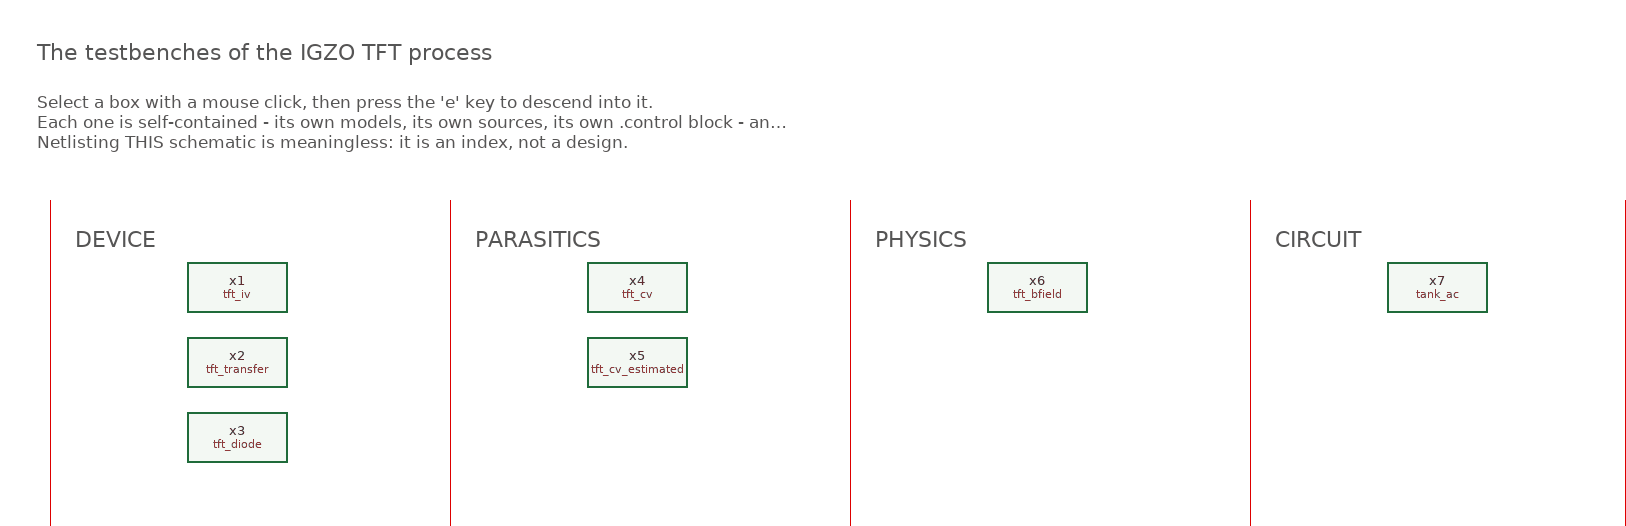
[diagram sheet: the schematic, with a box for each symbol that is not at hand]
v {xschem version=3.4.5 file_version=1.2

* The testbenches of the UCI/INRF IGZO TFT process (igzo_mmm_lab).
*
* Licensed under the Apache License, Version 2.0 (the "License");
* you may not use this file except in compliance with the License.
* You may obtain a copy of the License at
*
*     http://www.apache.org/licenses/LICENSE-2.0
*
* GENERATED by scripts/build_test_symbols.py - do not edit by hand.
}
G {}
K {}
V {}
S {}
E {}
L 7 40 -710 40 -80 {}
T {DEVICE} 60 -690 0 0 0.7 0.7 {}
L 7 360 -710 360 -80 {}
T {PARASITICS} 380 -690 0 0 0.7 0.7 {}
L 7 680 -710 680 -80 {}
T {PHYSICS} 700 -690 0 0 0.7 0.7 {}
L 7 1000 -710 1000 -80 {}
T {CIRCUIT} 1020 -690 0 0 0.7 0.7 {}
L 7 1300 -710 1300 -80 {}
T {The testbenches of the IGZO TFT process} 30 -840 0 0 0.8 0.8 {layer=8}
T {Select a box with a mouse click, then press the 'e' key to descend into it.
Each one is self-contained - its own models, its own sources, its own .control block - and prints what it measured.
Netlisting THIS schematic is meaningless: it is an index, not a design.} 30 -800 0 0 0.4 0.4 {layer=11}
C {tests/tft_iv.sym} 190 -640 0 0 {name=x1}
C {tests/tft_transfer.sym} 190 -580 0 0 {name=x2}
C {tests/tft_diode.sym} 190 -520 0 0 {name=x3}
C {tests/tft_cv.sym} 510 -640 0 0 {name=x4}
C {tests/tft_cv_estimated.sym} 510 -580 0 0 {name=x5}
C {tests/tft_bfield.sym} 830 -640 0 0 {name=x6}
C {tests/tank_ac.sym} 1150 -640 0 0 {name=x7}
C {devices/title.sym} 160 -30 0 0 {name=l1 author="UCI/INRF - MMM Lab"}
C {devices/launcher.sym} 30 -890 0 0 {name=h1
descr="TFT-MMM-LAB-PDK on GitHub"
url="https://github.com/Juander28/TFT-MMM-LAB-PDK"}
